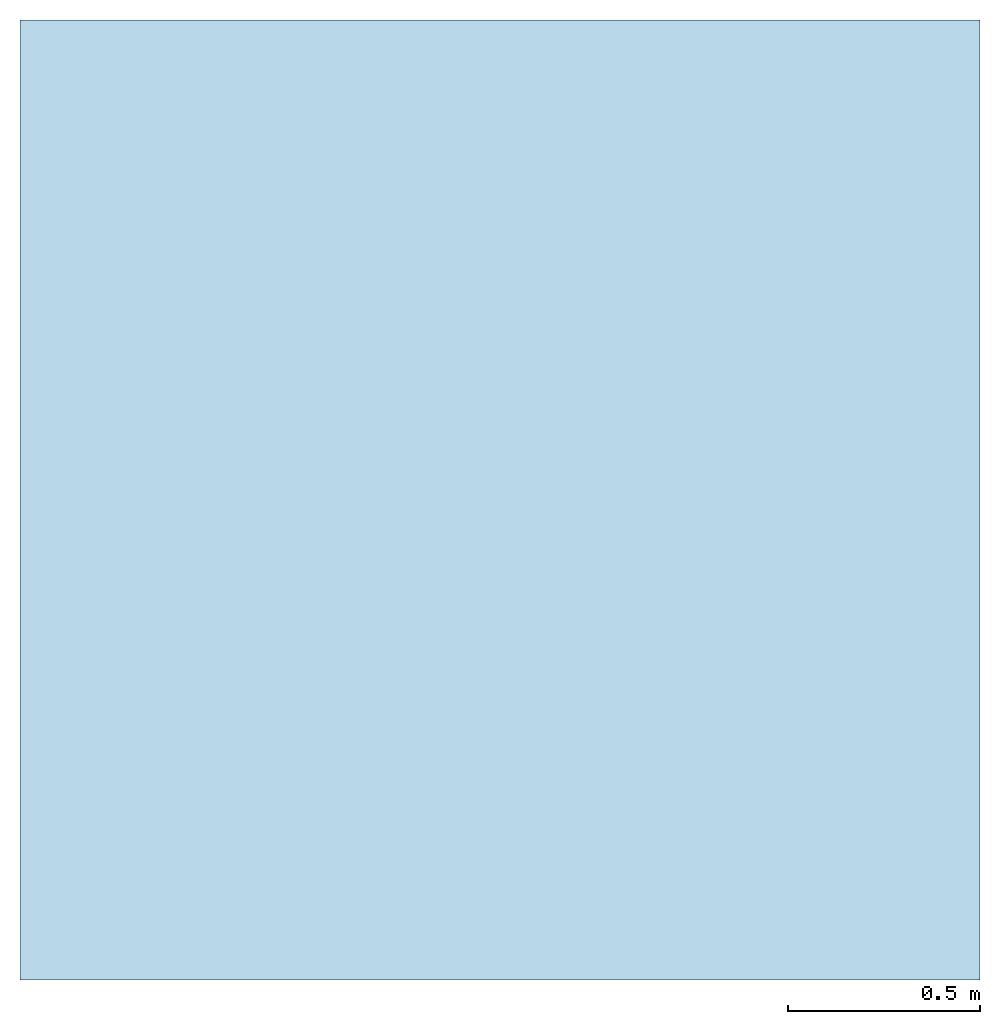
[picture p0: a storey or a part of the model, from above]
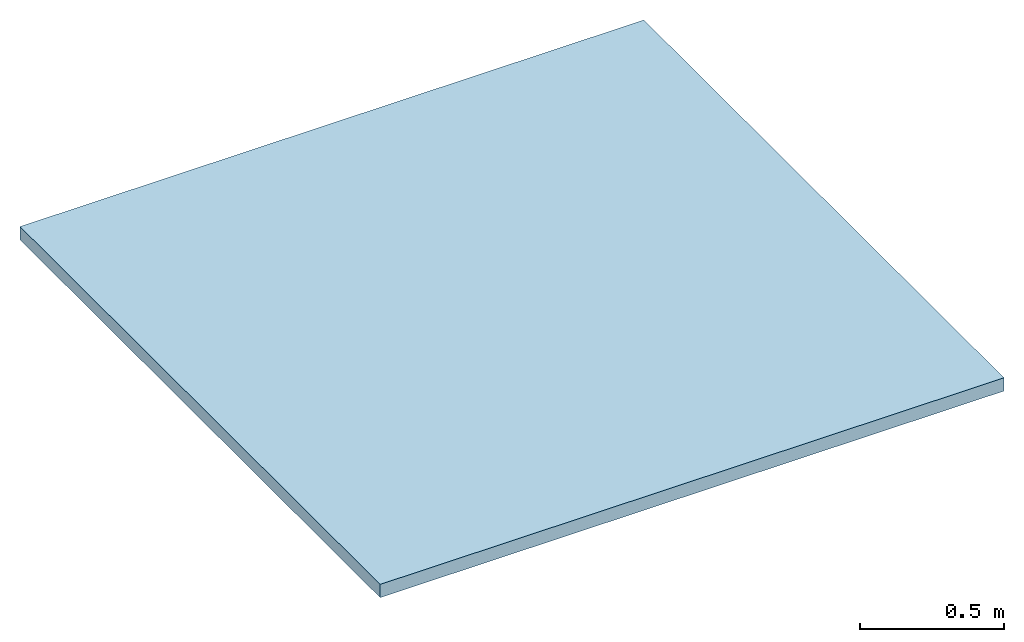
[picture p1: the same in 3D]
Properties of the parts of a building model (IFC2X3)

# File
Description: ViewDefinition [CoordinationView_V2.0]
File name: Project Number
Time: 2025-08-25T15:16:55
Written by: ODA IFC SDK 22.8
Made in: 22.1.70.9 - Exporter 22.4.0.0 - Alternate UI 22.4.0.0

# IfcProject, Project Number
LongName: Project Name; Phase: Project Status
COBie - Category: Project Information

# IfcSite, Default
RefLatitude: 51, 30, 0, 549316; RefLongitude: 0, -7, -34, -450321; RefElevation: 0 mm
COBie - Category: Project Information

# IfcBuilding
COBie - Category: Project Information

# IfcBuildingStorey: Level:Circle Head - Project Datum, Level 0
LongName: Level 0; Elevation: 0 mm
COBie - Category: Levels; Name: Level 0

# IfcRoof: Basic Roof:NBS_IKOUK_Liquid-appliedInvertedRoofCoveringSystems_-IKOPermatecLIStandardInvertedHotMeltRoofingAndWaterproofingSystem, Basic Roof:NBS_IKOUK_Liquid-appliedInvertedRoofCoveringSystems_-IKOPermatecLIStandardInvertedHotMeltRoofingAndWaterproofingSystem:221901
In: Level 0
ShapeType: FLAT_ROOF; Classification: Ss_30_40_30_42 (Uniclass2015); Material: NBS_IKOUK_Liquid-appliedInvertedRoofCoveringSystems_IKOPermatecLIStandardInvertedHotMeltRoofingAndWaterproofingSystem_IKOEnerthermWaterControlLayer 1 mm, NBS_IKOUK_Liquid-appliedInvertedRoofCoveringSystems_IKOPermatecLIStandardInvertedHotMeltRoofingAndWaterproofingSystem_IKOEnerthermXPSInsulationBoard 50 mm, NBS_IKOUK_Liquid-appliedInvertedRoofCoveringSystems_IKOPermatecLIStandardInvertedHotMeltRoofingAndWaterproofingSystem_IKOPermaguard-FProtectionLayer 1 mm, NBS_IKOUK_Liquid-appliedInvertedRoofCoveringSystems_IKOPermatecLIStandardInvertedHotMeltRoofingAndWaterproofingSystem_IKOPermaflash-RReinforcement 1 mm, NBS_IKOUK_Liquid-appliedInvertedRoofCoveringSystems_IKOPermatecLIStandardInvertedHotMeltRoofingAndWaterproofingSystem_2NoCoatsOfIKOPermatecLIEcowrapHotMeltCompound 1 mm, NBS_IKOUK_Liquid-appliedInvertedRoofCoveringSystems_IKOPermatecLIStandardInvertedHotMeltRoofingAndWaterproofingSystem_IKOPermatecPolymerPrimer 1 mm, NBS_IKOUK_Liquid-appliedInvertedRoofCoveringSystems_IKOPermatecLIStandardInvertedHotMeltRoofingAndWaterproofingSystem_IKOPermatecPolymerPrimer 1 mm
IFC - IfcExportAs: IfcRoofType; IfcExportType: FLAT_ROOF
COBie - AccessibilityPerformance: n/a; AssetIdentifier: n/a; AssetType: Fixed; BarCode: n/a; Category: Ss_30_40_30_42:Liquid-applied inverted roof covering systems; Color: n/a; Finish: n/a; Material: Bitumen; Shape: n/a; Size: n/a; WarrantyDescription: 25 year; CodePerformance: n/a; Constituents: n/a; Description: Hot melt bitumen membrane roofing and waterproofing system.; DurationUnit: year; ExpectedLife: 60 year; Features: n/a; Grade: n/a; InstallationDate: 1900-12-31T23:59:59; Manufacturer: marketing.uk@iko.com; ModelNumber: n/a; ModelReference: Over 50% Lower Embodied Carbon - IKO Permatec LI Standard Inverted Hot Melt Roofing & Waterproofing System; Name: Liquid-appliedInvertedRoofCoveringSystems_-IKOPermatecLIStandardInvertedHotMeltRoofingAndWaterproofingSystem_IKOUK; NominalHeight: 0 mm; NominalLength: 0 mm; NominalWidth: 0 mm; ReplacementCost: n/a; SerialNumber: n/a; SustainabilityPerformance: n/a; TagNumber: n/a; WarrantyDurationLabor: n/a; WarrantyDurationParts: n/a; WarrantyDurationUnit: year; WarrantyGuarantorLabor: n/a; WarrantyGuarantorParts: n/a; WarrantyStartDate: 1900-12-31T23:59:59
BOS_General - Author: NBS; BIMObjectName: NBS_IKOUK_Liquid-appliedInvertedRoofCoveringSystems_IKOPermatecLIStandardInvertedHotMeltRoofingAndWaterproofingSystem; ManufacturerName: IKO UK; ManufacturerURL: https://ikogroup.co.uk/; ProductInformation: https://source.thenbs.com/product/-/94945cc9-5567-4a40-bd7e-4a80e9aff6f1/2a645743-daa6-4da0-abc5-f41af6819c48; Uniclass2015Code: Ss_30_40_30_42; Uniclass2015Title: Liquid-applied inverted roof covering systems; Uniclass2015Version: Systems v1.37; Version: 11
NBS_Data - A1-A3ProductionStage: 1.61; ContainsRedListMaterials: Yes; CountryOfMaterialOrigin: United Kingdom; CountryOfProductManufacture: United Kingdom; DrainageLayer: Not required,Required; FlashingsAndDetailWork: Not required,IKO PermaFLASH-D150,IKO PermaFLASH-D500,IKO PermaFLASH-UN; InsulationType: IKO enertherm XPS insulation board; Liquid-appliedWaterproofingType: 2 no. coats of IKO Permatec LI Ecowrap hot melt compound,2 no. coats of IKO Permatec LI Ecowrap hot melt compound, plus IKO Permaguard-HDPB (Heavy Duty),2 no. coats of IKO Permatec LI Ecowrap hot melt compound, plus IKO Permaguard-PB; Liquid-appliedWaterproofingReinforcement: IKO Permaflash-R reinforcement; Liquid-appliedWaterproofingSurfaceTreatment: IKO Permaguard-F protection layer,IKO Roofgarden 4 APP AD/F; ManufacturingPlantLocation: Grangemill, Matlock DE4 4HU, UK; PreparationHorizontalWork: IKO Permatec Polymer Primer,IKO Permatec high penetration primer; PreparationSkirtingsAndVerticalWork: IKO Permatec Polymer Primer,IKO Permatec high penetration primer; RecycledContent: 45; Upstand: Exposed upstand details: IKO PermaGUARD-M Torch On (T-O) protection layer; WaterControlLayer: IKO enertherm water control layer

# IfcSlab: Basic Roof:NBS_IKOUK_Liquid-appliedInvertedRoofCoveringSystems_-IKOPermatecLIStandardInvertedHotMeltRoofingAndWaterproofingSystem, Basic Roof:NBS_IKOUK_Liquid-appliedInvertedRoofCoveringSystems_-IKOPermatecLIStandardInvertedHotMeltRoofingAndWaterproofingSystem:221901
In: Level 0
Type - PredefinedType: ROOF
Type - IFC - IfcExportAs: IfcRoofType; IfcExportType: FLAT_ROOF
Type - COBie - NominalHeight: 0 mm; NominalLength: 0 mm; NominalWidth: 0 mm; AccessibilityPerformance: n/a; AssetType: Fixed; Category: Ss_30_40_30_42:Liquid-applied inverted roof covering systems; Color: n/a; Finish: n/a; Material: Bitumen; Shape: n/a; Size: n/a; WarrantyDescription: 25 year; CodePerformance: n/a; Constituents: n/a; Description: Hot melt bitumen membrane roofing and waterproofing system.; DurationUnit: year; ExpectedLife: 60 year; Features: n/a; Grade: n/a; Manufacturer: marketing.uk@iko.com; ModelNumber: n/a; ModelReference: Over 50% Lower Embodied Carbon - IKO Permatec LI Standard Inverted Hot Melt Roofing & Waterproofing System; Name: Liquid-appliedInvertedRoofCoveringSystems_-IKOPermatecLIStandardInvertedHotMeltRoofingAndWaterproofingSystem_IKOUK; ReplacementCost: n/a; SustainabilityPerformance: n/a; WarrantyDurationLabor: n/a; WarrantyDurationParts: n/a; WarrantyDurationUnit: year; WarrantyGuarantorLabor: n/a; WarrantyGuarantorParts: n/a
Type - BOS_General - Author: NBS; BIMObjectName: NBS_IKOUK_Liquid-appliedInvertedRoofCoveringSystems_IKOPermatecLIStandardInvertedHotMeltRoofingAndWaterproofingSystem; ManufacturerName: IKO UK; ManufacturerURL: https://ikogroup.co.uk/; ProductInformation: https://source.thenbs.com/product/-/94945cc9-5567-4a40-bd7e-4a80e9aff6f1/2a645743-daa6-4da0-abc5-f41af6819c48; Uniclass2015Code: Ss_30_40_30_42; Uniclass2015Title: Liquid-applied inverted roof covering systems; Uniclass2015Version: Systems v1.37; Version: 11
Type - NBS_Data - A1-A3ProductionStage: 1.61; ContainsRedListMaterials: Yes; CountryOfMaterialOrigin: United Kingdom; CountryOfProductManufacture: United Kingdom; DrainageLayer: Not required,Required; FlashingsAndDetailWork: Not required,IKO PermaFLASH-D150,IKO PermaFLASH-D500,IKO PermaFLASH-UN; InsulationType: IKO enertherm XPS insulation board; Liquid-appliedWaterproofingType: 2 no. coats of IKO Permatec LI Ecowrap hot melt compound,2 no. coats of IKO Permatec LI Ecowrap hot melt compound, plus IKO Permaguard-HDPB (Heavy Duty),2 no. coats of IKO Permatec LI Ecowrap hot melt compound, plus IKO Permaguard-PB; Liquid-appliedWaterproofingReinforcement: IKO Permaflash-R reinforcement; Liquid-appliedWaterproofingSurfaceTreatment: IKO Permaguard-F protection layer,IKO Roofgarden 4 APP AD/F; ManufacturingPlantLocation: Grangemill, Matlock DE4 4HU, UK; PreparationHorizontalWork: IKO Permatec Polymer Primer,IKO Permatec high penetration primer; PreparationSkirtingsAndVerticalWork: IKO Permatec Polymer Primer,IKO Permatec high penetration primer; RecycledContent: 45; Upstand: Exposed upstand details: IKO PermaGUARD-M Torch On (T-O) protection layer; WaterControlLayer: IKO enertherm water control layer
Classification: Ss_30_40_30_42 (Uniclass2015); Material: NBS_IKOUK_Liquid-appliedInvertedRoofCoveringSystems_IKOPermatecLIStandardInvertedHotMeltRoofingAndWaterproofingSystem_IKOEnerthermWaterControlLayer 1 mm, NBS_IKOUK_Liquid-appliedInvertedRoofCoveringSystems_IKOPermatecLIStandardInvertedHotMeltRoofingAndWaterproofingSystem_IKOEnerthermXPSInsulationBoard 50 mm, NBS_IKOUK_Liquid-appliedInvertedRoofCoveringSystems_IKOPermatecLIStandardInvertedHotMeltRoofingAndWaterproofingSystem_IKOPermaguard-FProtectionLayer 1 mm, NBS_IKOUK_Liquid-appliedInvertedRoofCoveringSystems_IKOPermatecLIStandardInvertedHotMeltRoofingAndWaterproofingSystem_IKOPermaflash-RReinforcement 1 mm, NBS_IKOUK_Liquid-appliedInvertedRoofCoveringSystems_IKOPermatecLIStandardInvertedHotMeltRoofingAndWaterproofingSystem_2NoCoatsOfIKOPermatecLIEcowrapHotMeltCompound 1 mm, NBS_IKOUK_Liquid-appliedInvertedRoofCoveringSystems_IKOPermatecLIStandardInvertedHotMeltRoofingAndWaterproofingSystem_IKOPermatecPolymerPrimer 1 mm, NBS_IKOUK_Liquid-appliedInvertedRoofCoveringSystems_IKOPermatecLIStandardInvertedHotMeltRoofingAndWaterproofingSystem_IKOPermatecPolymerPrimer 1 mm
COBie - AssetIdentifier: n/a; BarCode: n/a; InstallationDate: 1900-12-31T23:59:59; SerialNumber: n/a; TagNumber: n/a; WarrantyStartDate: 1900-12-31T23:59:59
